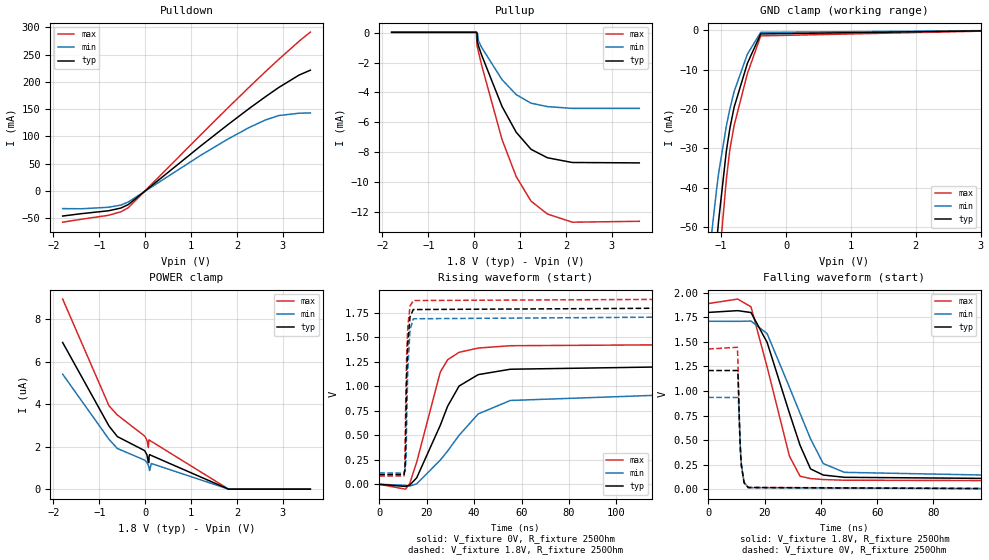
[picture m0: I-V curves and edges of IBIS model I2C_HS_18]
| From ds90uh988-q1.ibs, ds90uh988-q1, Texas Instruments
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[Model]   I2C_HS_18
Model_type   I/O
Polarity   Non-Inverting
Enable   Active-High
Vinl = 0.54
Vinh = 1.26
Vmeas = 0.9
Vref = 1.8
Cref = 0pF
Rref = 250
|   typ   min   max
C_comp   1.3293528pF  1.3920023pF  1.3293528pF
[Voltage Range]   1.8   1.71   1.89
[Temperature Range]   27   105   -40
[Pullup Reference]   1.8   1.71   1.89
[Pulldown Reference]   0   -0   0
[Power Clamp Reference]   1.8   1.71   1.89
[GND Clamp Reference]   0   0   0
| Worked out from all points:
|   slope of the pulldown table from 0 to 0.27 V, typ, clamps not added: 14.5 ohm
|   slope of the pullup table from 0 to 0.27 V, typ, clamps not added: 110 ohm
|   GND clamp passes 1 mA (typ) near -0.39 V on its own axis
|   falling waveform, V_fixture 1.8V, R_fixture 250Ohm: 20-80 % time 11.4ns typ, 13.4ns min, 9.17ns max; typ from 1.8 V to 0.099 V
|   rising waveform, V_fixture 0V, R_fixture 250Ohm: 20-80 % time 13.2ns typ, 19.9ns min, 9.24ns max; typ from 0 V to 1.21 V
|   rising waveform, V_fixture 1.8V, R_fixture 250Ohm: 20-80 % time 943ps typ, 953ps min, 936ps max; typ from 0.099 V to 1.8 V
|   falling waveform, V_fixture 0V, R_fixture 250Ohm: 20-80 % time 994ps typ, 1.03ns min, 970ps max; typ from 1.21 V to 0 V
[Pulldown]
|   Voltage   I(typ)   I(min)   I(max)
-1.8V     -46.05mA   -32.39mA   -57.33mA
-1.39V    -41.67mA   -32.67mA   -51.89mA
-801mV    -36.39mA   -29.97mA   -44.68mA
-531mV    -31.37mA   -25.98mA   -38.26mA
-369mV    -25.03mA   -20.3mA    -30.81mA
1.219V    83.16mA    65.87mA    103.7mA
1.796V    121.2mA    94.83mA    151.9mA
2.266V    151.2mA    116.4mA    190.4mA
2.628V    173.3mA    130.5mA    219.4mA
2.909V    189.7mA    138.3mA    241.3mA
3.352V    212.5mA    142.6mA    274.5mA
3.6V      221.6mA    143.2mA    291.5mA
[GND Clamp]
|   Voltage   I(typ)   I(min)   I(max)
-1.8V     -199.4mA   -169.6mA   -233.1mA
-1.217V   -81.45mA   -62.71mA   -99.08mA
-1.195V   -77.25mA   -59.17mA   -94.26mA
-1.163V   -71.03mA   -53.98mA   -87.07mA
-1.071V   -54.02mA   -40.47mA   -67.16mA
-1.039V   -48.35mA   -36.29mA   -60.36mA
-919.8mV  -30.64mA   -24.24mA   -37.84mA
-865.8mV  -24.89mA   -19.99mA   -30.25mA
-801mV    -19.58mA   -15.58mA   -24.22mA
-595.8mV  -8.39mA    -6.051mA   -11mA
-390.6mV  -916.2uA   -527.9uA   -1.415mA
3.6V      0A         0A         0A
[Pullup]
|   Voltage   I(typ)   I(min)   I(max)
-1.8V     33.71uA    22.86uA    49.36uA
46.8mV    33.14uA    22.54uA    48.18uA
63mV      -35.99uA   22.5uA     -855.2uA
68.4mV    -585.8uA   22.48uA    -935.9uA
95.4mV    -892.2uA   -546.7uA   -1.295mA
160.2mV   -1.475mA   -964.1uA   -2.142mA
608.4mV   -4.946mA   -3.146mA   -7.167mA
916.2mV   -6.667mA   -4.143mA   -9.64mA
1.24V     -7.813mA   -4.72mA    -11.29mA
1.597V    -8.379mA   -4.948mA   -12.15mA
2.137V    -8.696mA   -5.068mA   -12.7mA
3.6V      -8.723mA   -5.067mA   -12.64mA
[POWER Clamp]
|   Voltage   I(typ)   I(min)   I(max)
-1.8V     6.905uA    5.414uA    8.951uA
-790.2mV  2.974uA    2.348uA    3.928uA
-606.6mV  2.475uA    1.914uA    3.491uA
-12.6mV   1.815uA    1.368uA    2.501uA
36mV      1.629uA    1.267uA    2.314uA
68.4mV    1.266uA    1.118uA    1.957uA
79.2mV    1.249uA    1.038uA    2.31uA
84.6mV    1.541uA    990nA      2.319uA
95.4mV    1.629uA    877.6nA    2.303uA
133.2mV   1.587uA    1.209uA    2.25uA
1.818V    0A         0A         1.266nA
3.6V      0A         0A         0A
[Ramp]
R_load = 250
|   typ   min   max
dV/dt_r   0.725034/1.32523e-08   0.56049/1.97826e-08   0.856128/9.24308e-09
dV/dt_f   1.02057/1.13744e-08   0.956043/1.33627e-08   1.08334/9.12992e-09
[Falling Waveform]
V_fixture = 1.8V
V_fixture_min = 1.71V
V_fixture_max = 1.89V
R_fixture = 250Ohm
C_fixture = 0F
|   Time   V(typ)   V(min)   V(max)
0s        1.8V       1.71V      1.89V
10.47ns   1.818V     1.709V     1.936V
15.2ns    1.799V     1.712V     1.857V
20.92ns   1.495V     1.584V     1.245V
28.85ns   774.7mV    1.038V     335.9mV
32.62ns   446.8mV    771.8mV    131.8mV
36.35ns   206.2mV    511.7mV    108mV
40.86ns   143.8mV    260.7mV    98.04mV
48.37ns   120.7mV    171.4mV    91.1mV
147ns     98.9mV     116.4mV    84.29mV
[Rising Waveform]
V_fixture = 0V
V_fixture_min = 0V
V_fixture_max = 0V
R_fixture = 250Ohm
C_fixture = 0F
|   Time   V(typ)   V(min)   V(max)
0s        4.007uV    6.368uV    2.353uV
11.05ns   -21.58mV   -10.45mV   -49.66mV
12.81ns   -9.809mV   -18.64mV   5.197mV
15.81ns   66.67mV    4.786mV    227.4mV
25.74ns   601.8mV    246.9mV    1.145V
28.85ns   797.2mV    339.7mV    1.271V
33.69ns   1.003V     500.6mV    1.347V
41.74ns   1.119V     718.2mV    1.39V
55.26ns   1.174V     855.3mV    1.414V
147ns     1.208V     934.2mV    1.427V
[Rising Waveform]
V_fixture = 1.8V
V_fixture_min = 1.71V
V_fixture_max = 1.89V
R_fixture = 250Ohm
C_fixture = 0F
|   Time   V(typ)   V(min)   V(max)
0s        98.91mV    116.4mV    84.29mV
10.44ns   99.91mV    113.6mV    86.06mV
10.8ns    142.6mV    141.1mV    174.2mV
11.04ns   263.6mV    172.8mV    641.5mV
11.32ns   756.6mV    268.3mV    1.066V
11.63ns   1.141V     711.6mV    1.371V
12.03ns   1.432V     1.157V     1.603V
12.97ns   1.709V     1.576V     1.817V
14.36ns   1.783V     1.689V     1.875V
147ns     1.8V       1.71V      1.89V
[Falling Waveform]
|Gnd
V_fixture = 0V
V_fixture_min = 0V
V_fixture_max = 0V
R_fixture = 250Ohm
C_fixture = 0F
|   Time   V(typ)   V(min)   V(max)
0s        1.208V     934.2mV    1.427V
10.37ns   1.208V     933.9mV    1.445V
10.53ns   1.205V     934.2mV    1.33V
10.73ns   1.031V     926.6mV    1.089V
11.21ns   561.2mV    579.5mV    551.9mV
11.51ns   359mV      379.4mV    352.3mV
11.8ns    238.8mV    254.6mV    232.5mV
12.75ns   66.16mV    69.57mV    65.41mV
14.21ns   16.63mV    15.31mV    18.05mV
147ns     3.999uV    6.367uV    2.353uV
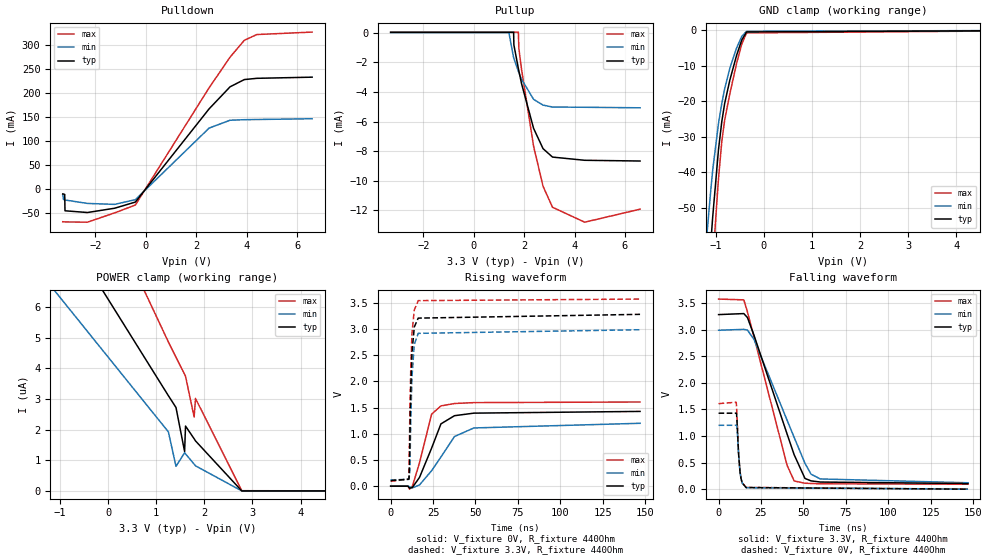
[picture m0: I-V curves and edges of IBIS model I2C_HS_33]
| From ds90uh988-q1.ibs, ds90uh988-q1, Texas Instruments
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[Model]   I2C_HS_33
Model_type   I/O
Polarity   Non-Inverting
Enable   Active-High
Vinl = 0.99
Vinh = 2.31
Vmeas = 1.65
Vref = 3.3
Cref = 0pF
Rref = 440
|   typ   min   max
C_comp   1.392003pF   1.392003pF   1.392003pF
[Voltage Range]   3.3   3   3.6
[Temperature Range]   27   105   -40
[Pullup Reference]   3.3   3   3.6
[Pulldown Reference]   -0   -0   0
[Power Clamp Reference]   3.3   3   3.6
[GND Clamp Reference]   0   0   0
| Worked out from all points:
|   slope of the pulldown table from 0 to 0.495 V, typ, clamps not added: 14.5 ohm
|   GND clamp passes 1 mA (typ) near -0.39 V on its own axis
|   falling waveform, V_fixture 3.3V, R_fixture 440Ohm: 20-80 % time 20ns typ, 21.9ns min, 16.8ns max; typ from 3.28 V to 0.106 V
|   rising waveform, V_fixture 0V, R_fixture 440Ohm: 20-80 % time 10.2ns typ, 15.2ns min, 7.22ns max; typ from 0 V to 1.43 V
|   rising waveform, V_fixture 3.3V, R_fixture 440Ohm: 20-80 % time 1.48ns typ, 1.49ns min, 1.46ns max; typ from 0.106 V to 3.28 V
|   falling waveform, V_fixture 0V, R_fixture 440Ohm: 20-80 % time 1.71ns typ, 1.76ns min, 1.68ns max; typ from 1.43 V to 0 V
[Pulldown]
|   Voltage   I(typ)   I(min)   I(max)
-3.3V     -10.64mA   -11.81mA   -68.38mA
-3.27V    -10.82mA   -22.15mA   -68.51mA
-3.221V   -11.72mA   -23.04mA   -68.72mA
-3.211V   -45.64mA   -23.2mA    -68.77mA
-2.32V    -49.24mA   -30.33mA   -69.34mA
-1.241V   -40.33mA   -32.32mA   -49.99mA
-419.1mV  -27.53mA   -22.53mA   -33.72mA
2.511V    166.3mA    126.3mA    210.1mA
3.343V    212.1mA    142.6mA    273.8mA
3.907V    227.1mA    143.7mA    308.7mA
4.402V    229.7mA    144.1mA    320.7mA
6.6V      232.1mA    145.7mA    325.8mA
[GND Clamp]
|   Voltage   I(typ)   I(min)   I(max)
-3.3V     -528.6mA   -466.9mA   -595.9mA
-1.211V   -80.34mA   -61.77mA   -97.81mA
-1.102V   -59.67mA   -44.82mA   -73.84mA
-1.063V   -52.53mA   -39.35mA   -65.39mA
-943.8mV  -33.69mA   -26.31mA   -41.91mA
-874.5mV  -25.73mA   -20.64mA   -31.31mA
-815.1mV  -20.61mA   -16.48mA   -25.31mA
-706.2mV  -13.96mA   -10.63mA   -17.82mA
-567.6mV  -7.079mA   -5.004mA   -9.374mA
-458.7mV  -2.703mA   -1.686mA   -3.845mA
-359.7mV  -460.5uA   -270uA     -723.2uA
6.6V      0A         0A         0A
[Pullup]
|   Voltage   I(typ)   I(min)   I(max)
-3.3V     35.28uA    23.9uA     51.52uA
1.393V    33.27uA    21.97uA    48.86uA
1.581V    31.9uA     -1.681mA   48.79uA
1.591V    -813.3uA   -1.733mA   48.78uA
1.769V    -2.41mA    -2.599mA   48.32uA
1.789V    -2.575mA   -2.688mA   -1.059mA
1.897V    -3.444mA   -3.143mA   -2.49mA
2.373V    -6.46mA    -4.498mA   -7.665mA
2.749V    -7.835mA   -4.888mA   -10.38mA
3.125V    -8.405mA   -5.02mA    -11.8mA
4.402V    -8.622mA   -5.035mA   -12.81mA
6.6V      -8.671mA   -5.071mA   -11.93mA
[POWER Clamp]
|   Voltage   I(typ)   I(min)   I(max)
-3.3V     42.87uA    22.78uA    77.21uA
-2.993V   23.33uA    15.21uA    37.79uA
-2.488V   14.76uA    10.86uA    22.03uA
-1.419V   9.829uA    7.138uA    13.8uA
1.254V    3.108uA    1.927uA    4.861uA
1.412V    2.723uA    803.9nA    4.365uA
1.591V    1.286uA    1.246uA    3.805uA
1.61V     2.116uA    1.209uA    3.742uA
1.789V    1.703uA    874.7nA    2.412uA
1.818V    1.632uA    819.1nA    3.018uA
2.779V    0A         0A         7.004nA
6.6V      0A         0A         0A
[Ramp]
R_load = 440
|   typ   min   max
dV/dt_r   0.856665/1.0188e-08   0.720539/1.51366e-08   0.964776/7.22213e-09
dV/dt_f   1.90598/2.00138e-08   1.72062/2.19193e-08   2.08876/1.68093e-08
[Falling Waveform]
V_fixture = 3.3V
V_fixture_min = 3V
V_fixture_max = 3.6V
R_fixture = 440Ohm
C_fixture = 0F
|   Time   V(typ)   V(min)   V(max)
0s        3.282V     2.988V     3.574V
14.88ns   3.301V     3.004V     3.559V
17ns      3.227V     2.991V     3.334V
20.94ns   2.888V     2.812V     2.853V
40.36ns   1.039V     1.298V     450.4mV
44.54ns   648mV      974.2mV    154.8mV
50.92ns   201.5mV    486.7mV    111.4mV
54.51ns   155.7mV    281.3mV    107.1mV
59.97ns   133.9mV    192.2mV    101mV
147ns     105.8mV    120.3mV    93.14mV
[Rising Waveform]
V_fixture = 0V
V_fixture_min = 0V
V_fixture_max = 0V
R_fixture = 440Ohm
C_fixture = 0F
|   Time   V(typ)   V(min)   V(max)
0s        29.02uV    29.52uV    30.06uV
10.17ns   38.06uV    -3.728uV   13.59uV
11.16ns   -38.4mV    -10.47mV   -57.27mV
12.78ns   -25.52mV   -32.17mV   -3.649mV
17ns      166.9mV    23.37mV    445.8mV
24.15ns   727.8mV    296.7mV    1.376V
29.63ns   1.19V      556.9mV    1.533V
37.62ns   1.346V     948.6mV    1.579V
49.05ns   1.395V     1.112V     1.596V
147ns     1.428V     1.201V     1.608V
[Rising Waveform]
V_fixture = 3.3V
V_fixture_min = 3V
V_fixture_max = 3.6V
R_fixture = 440Ohm
C_fixture = 0F
|   Time   V(typ)   V(min)   V(max)
0s        105.8mV    120.3mV    93.15mV
10.67ns   134mV      129mV      133.3mV
10.82ns   157.8mV    150.9mV    234.7mV
10.96ns   217.5mV    177.4mV    599.4mV
11.31ns   908.2mV    303.8mV    1.39V
11.9ns    1.892V     1.314V     2.326V
12.57ns   2.549V     2.091V     2.922V
13.92ns   3.04V      2.708V     3.364V
16.25ns   3.21V      2.919V     3.544V
147ns     3.282V     2.988V     3.574V
[Falling Waveform]
|Gnd
V_fixture = 0V
V_fixture_min = 0V
V_fixture_max = 0V
R_fixture = 440Ohm
C_fixture = 0F
|   Time   V(typ)   V(min)   V(max)
0s        1.428V     1.201V     1.608V
10.4ns    1.428V     1.201V     1.635V
10.61ns   1.415V     1.202V     1.527V
10.85ns   1.282V     1.172V     1.376V
11.81ns   658.2mV    649.3mV    665.8mV
12.61ns   332.2mV    331.1mV    334.5mV
13.19ns   206.3mV    206.4mV    209.5mV
13.92ns   118mV      114.6mV    119.7mV
16.25ns   30.86mV    26.94mV    33.53mV
147ns     29.03uV    29.52uV    30.05uV
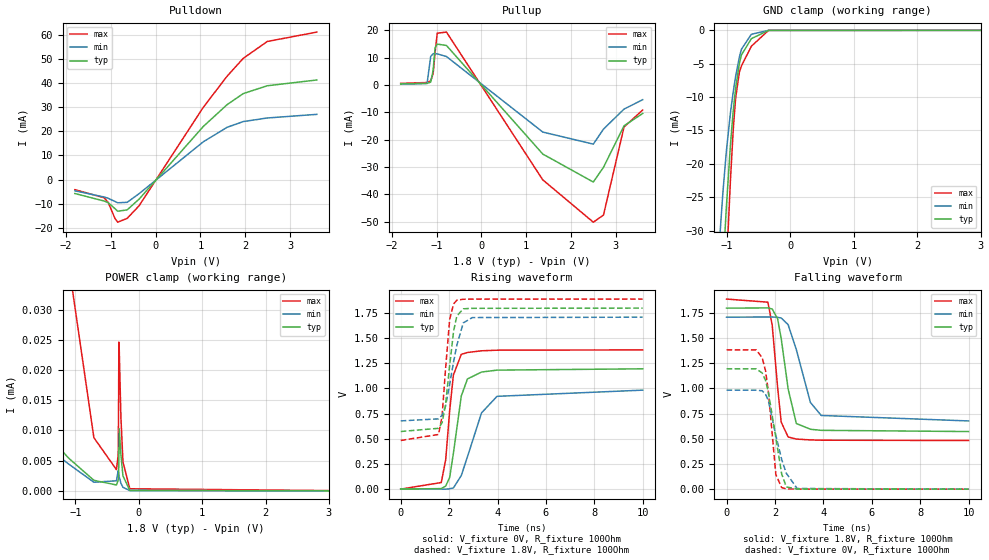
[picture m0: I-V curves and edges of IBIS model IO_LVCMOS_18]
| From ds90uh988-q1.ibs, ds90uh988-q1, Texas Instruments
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[Model]   IO_LVCMOS_18
Model_type   I/O
Polarity   Non-Inverting
Enable   Active-High
Vinl = 0.63
Vinh = 1.17
Vmeas = 0.9
Vref = 1.8
Cref = 0pF
Rref = 100000
|   typ   min   max
C_comp   1.106pF   1.158pF   1.008pF
[Voltage Range]   1.8   1.71   1.89
[Temperature Range]   27   105   -40
[Pullup Reference]   1.8   1.71   1.89
[Pulldown Reference]   0   -0   -0
[Power Clamp Reference]   1.8   1.71   1.89
[GND Clamp Reference]   0   0   0
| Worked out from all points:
|   slope of the pulldown table from 0 to 0.27 V, typ, clamps not added: 45.8 ohm
|   slope of the pullup table from 0 to 0.27 V, typ, clamps not added: 49.3 ohm
|   GND clamp passes 1 mA (typ) near -0.58 V on its own axis
|   falling waveform, V_fixture 1.8V, R_fixture 100Ohm: 20-80 % time 440ps typ, 680ps min, 310ps max; typ from 1.8 V to 0.572 V
|   rising waveform, V_fixture 0V, R_fixture 100Ohm: 20-80 % time 416ps typ, 805ps min, 310ps max; typ from 0 V to 1.2 V
|   rising waveform, V_fixture 1.8V, R_fixture 100Ohm: 20-80 % time 336ps typ, 482ps min, 258ps max; typ from 0.572 V to 1.8 V
|   falling waveform, V_fixture 0V, R_fixture 100Ohm: 20-80 % time 484ps typ, 583ps min, 324ps max; typ from 1.2 V to 0 V
[Pulldown]
|   Voltage   I(typ)   I(min)   I(max)
-1.8V     -5.793mA   -4.665mA   -4.184mA
-1.147V   -8.908mA   -7.239mA   -7.547mA
-1.055V   -9.625mA   -7.782mA   -9.57mA
-903.6mV  -12.1mA    -9.086mA   -16.21mA
-844.2mV  -13.14mA   -9.64mA    -17.69mA
-633.6mV  -12.59mA   -9.447mA   -16.11mA
-369mV    -8.155mA   -5.888mA   -10.92mA
1.067V    22.05mA    15.68mA    30.01mA
1.597V    31.08mA    21.68mA    42.89mA
1.958V    35.68mA    24.06mA    50.31mA
2.493V    38.92mA    25.55mA    57.29mA
3.6V      41.32mA    27.06mA    61.19mA
[GND Clamp]
|   Voltage   I(typ)   I(min)   I(max)
-1.8V     -184.2mA   -145.6mA   -235.9mA
-1.13V    -47.5mA    -32.9mA    -63.91mA
-1.066V   -35.65mA   -24.24mA   -48.18mA
-1.012V   -26.52mA   -18.11mA   -35.76mA
-946.8mV  -17.06mA   -12.3mA    -22.32mA
-903.6mV  -12.08mA   -9.215mA   -14.91mA
-865.8mV  -8.679mA   -6.91mA    -10.13mA
-806.4mV  -4.938mA   -3.995mA   -6.267mA
-774mV    -3.689mA   -2.832mA   -5.339mA
-617.4mV  -1.25mA    -592.1uA   -2.383mA
-347.4mV  -7.545uA   -5.629uA   -16.55uA
3.6V      0A         0A         0A
[Pullup]
|   Voltage   I(typ)   I(min)   I(max)
-1.8V     361.5uA    237.4uA    543.1uA
-1.211V   533.9uA    553.1uA    865.1uA
-1.13V    1.025mA    10.44mA    1.5mA
-1.076V   5.331mA    11.37mA    4.179mA
-1.033V   13.58mA    11.44mA    11.77mA
-984.6mV  14.91mA    11.34mA    18.9mA
-779.4mV  14.41mA    10.37mA    19.3mA
1.37V     -25.28mA   -17.24mA   -34.71mA
2.498V    -35.51mA   -21.65mA   -50.19mA
2.725V    -30.12mA   -16.17mA   -47.57mA
3.184V    -14.96mA   -8.84mA    -15.38mA
3.6V      -10.45mA   -5.422mA   -9.185mA
[POWER Clamp]
|   Voltage   I(typ)   I(min)   I(max)
-1.8V     13.66uA    10.25uA    278uA
-1.114V   5.489uA    4.497uA    38.07uA
-709.2mV  1.756uA    1.437uA    8.807uA
-352.8mV  986.4nA    1.676uA    3.518uA
-325.8mV  1.774uA    3.345uA    5.996uA
-320.4mV  1.972uA    2.973uA    12.23uA
-315mV    4.52uA     2.638uA    24.64uA
-309.6mV  10.27uA    2.338uA    23.58uA
-282.6mV  5.962uA    1.265uA    12.12uA
-250.2mV  2.485uA    596.1nA    4.797uA
-142.2mV  94.31nA    55.99nA    357.4nA
3.6V      0A         0A         0A
[Ramp]
R_load = 100
|   typ   min   max
dV/dt_r   0.717257/4.15687e-10   0.589833/8.05112e-10   0.830028/3.0777e-10
dV/dt_f   0.735663/4.38638e-10   0.618535/6.76331e-10   0.843113/3.0958e-10
[Falling Waveform]
V_fixture = 1.8V
V_fixture_min = 1.71V
V_fixture_max = 1.89V
R_fixture = 100Ohm
C_fixture = 0F
|   Time   V(typ)   V(min)   V(max)
0s        1.798V     1.708V     1.888V
1.71ns    1.8V       1.71V      1.857V
1.887ns   1.789V     1.71V      1.629V
2.111ns   1.692V     1.707V     1.01V
2.259ns   1.496V     1.7V       665.5mV
2.545ns   996.2mV    1.634V     518.4mV
2.884ns   652.4mV    1.386V     497.4mV
3.465ns   595mV      861.7mV    489.2mV
3.914ns   584.3mV    731.9mV    486.4mV
10ns      572.2mV    677.6mV    483mV
[Rising Waveform]
V_fixture = 0V
V_fixture_min = 0V
V_fixture_max = 0V
R_fixture = 100Ohm
C_fixture = 0F
|   Time   V(typ)   V(min)   V(max)
0s        3.142uV    5.703uV    2.153uV
1.675ns   4.753mV    -660.7uV   65.16mV
1.859ns   29.99mV    -734uV     291.1mV
2.024ns   116.1mV    3.146mV    780.4mV
2.177ns   355.7mV    11.67mV    1.133V
2.503ns   924.2mV    134.6mV    1.339V
2.757ns   1.094V     320.5mV    1.357V
3.34ns    1.163V     757.1mV    1.374V
3.98ns    1.182V     921.6mV    1.38V
10ns      1.195V     983.1mV    1.383V
[Rising Waveform]
V_fixture = 1.8V
V_fixture_min = 1.71V
V_fixture_max = 1.89V
R_fixture = 100Ohm
C_fixture = 0F
|   Time   V(typ)   V(min)   V(max)
0s        572.2mV    677.6mV    483mV
1.563ns   603.9mV    697.7mV    542.8mV
1.71ns    659.3mV    733.5mV    723.7mV
1.849ns   830.3mV    820.1mV    1.181V
2.023ns   1.228V     1.041V     1.686V
2.187ns   1.571V     1.267V     1.84V
2.32ns    1.72V      1.43V      1.877V
2.586ns   1.791V     1.651V     1.886V
2.957ns   1.796V     1.704V     1.888V
10ns      1.798V     1.708V     1.888V
[Falling Waveform]
|Gnd
V_fixture = 0V
V_fixture_min = 0V
V_fixture_max = 0V
R_fixture = 100Ohm
C_fixture = 0F
|   Time   V(typ)   V(min)   V(max)
0s        1.195V     983.1mV    1.383V
1.226ns   1.195V     983mV      1.383V
1.473ns   1.154V     977.4mV    1.305V
1.611ns   1.08V      943.7mV    1.177V
1.73ns    961.8mV    877.7mV    965.7mV
2.038ns   511mV      533mV      144.6mV
2.278ns   152.1mV    295.8mV    15.68mV
2.47ns    22.4mV     157.5mV    3.114mV
2.918ns   1.47mV     6.809mV    723.6uV
10ns      3.573uV    6.654uV    2.262uV
